VERSION 5.7 ;
DIVIDERCHAR "/" ;
BUSBITCHARS "[]" ;

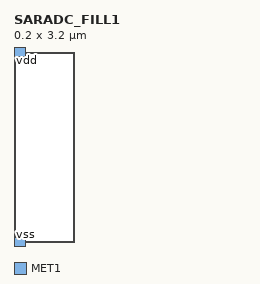
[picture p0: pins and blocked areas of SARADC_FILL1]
MACRO SARADC_FILL1
  CLASS BLOCK ;
  FOREIGN SARADC_FILL1 ;
  ORIGIN 0.000 0.000 ;
  SIZE 0.200 BY 3.200 ;
  SYMMETRY X Y R90 ;
  PIN vdd
    DIRECTION INOUT ;
    USE POWER ;
    PORT
      LAYER MET1 ;
        RECT 0.000 3.120 0.200 3.280 ;
    END
  END vdd
  PIN vss
    DIRECTION INOUT ;
    USE GROUND ;
    PORT
      LAYER MET1 ;
        RECT 0.000 -0.080 0.200 0.080 ;
    END
  END vss
END SARADC_FILL1

END LIBRARY
